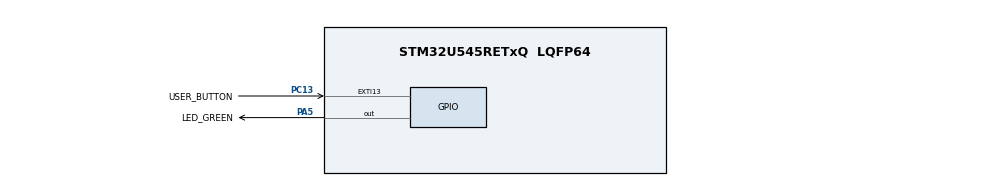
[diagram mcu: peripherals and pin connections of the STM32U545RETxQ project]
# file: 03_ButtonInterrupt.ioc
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CORTEX_M33_NS.userName=CORTEX_M33
Mcu.Family=STM32U5
Mcu.Name=STM32U545RETxQ
Mcu.Package=LQFP64
NVIC.EXTI13_IRQn=true\:0\:0\:false\:false\:true\:true\:true\:true
NVIC.PriorityGroup=NVIC_PRIORITYGROUP_4
PA5.GPIO_Label=LED_GREEN
PA5.GPIO_PuPd=GPIO_PULLUP
PA5.GPIO_Speed=GPIO_SPEED_FREQ_HIGH
PA5.Signal=GPIO_Output
PC13.GPIO_Label=USER_BUTTON
PC13.GPIO_ModeDefaultEXTI=GPIO_MODE_IT_FALLING
PC13.Signal=GPXTI13
PWR.PowerMode=PWR_SMPS_SUPPLY
ProjectManager.HeapSize=0x200
ProjectManager.StackSize=0x400
ProjectManager.TargetToolchain=STM32CubeIDE
RCC.ADCFreq_Value=16000000
RCC.DACCLockSelectionVirtual=RCC_DAC1CLKSOURCE_LSI
RCC.DACCLockSelectionVirtualString=RCC_DAC1CLKSOURCE_LSI
RCC.EPOD_VALUE=4000000
RCC.HSE_VALUE=16000000
RCC.HSI48_VALUE=48000000
RCC.HSI_VALUE=16000000
RCC.LSE_VALUE=32768
RCC.LSIDIV_VALUE=32000
RCC.MSI_VALUE=4000000
RCC.USBFreq_Value=48000000
RCC.VCOOutputFreq_Value=516000000
VP_ICACHE_VS_ICACHE.Mode=DirectMappedCache
VP_LPBAMQUEUE_VS_QUEUE.Mode=QUEUEMODE
VP_LPBAM_VS_SIG1.Mode=SmartRun
VP_LPBAM_VS_SIG4.Mode=LPDMA1
VP_MEMORYMAP_VS_MEMORYMAP.Mode=CurAppReg
VP_NUCLEO-U545RE-Q_VS_BSP_COMMON.Mode=COMMON
VP_PWR_VS_LPOM.Mode=PowerOptimisation
VP_PWR_VS_SECSignals.Mode=Security/Privilege
board=NUCLEO-U545RE-Q

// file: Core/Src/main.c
/* USER CODE BEGIN Header */
/**
 ******************************************************************************
 * @file           : main.c
 * @brief          : Main program body
 ******************************************************************************
 * @attention
 *
 * Copyright (c) 2025 STMicroelectronics.
 * All rights reserved.
 *
 * This software is licensed under terms that can be found in the LICENSE file
 * in the root directory of this software component.
 * If no LICENSE file comes with this software, it is provided AS-IS.
 *
 ******************************************************************************
 */
/* USER CODE END Header */
#include <CustomAssert.h>
#include "main.h"
#include "gpio.h"
#include "icache.h"

/* USER CODE BEGIN Includes */
#include "../../User_App/IsrHandler/IsrHandler.h"
#include "../../User_App/Profiler/Profiler.h"
#include "../../User_App/UserMain/UserMain.h"

/* USER CODE END Includes */

void SystemClock_Config(void);
static void SystemPower_Config(void);

int main(void) {

  /* MCU Configuration--------------------------------------------------------*/

  /* Reset of all peripherals, Initializes the Flash interface and the Systick.
   */
  HAL_Init();

  /* Configure the System Power */
  SystemPower_Config();

  /* Configure the system clock */
  SystemClock_Config();

  /* Initialize all configured peripherals */
  MX_GPIO_Init();
  MX_ICACHE_Init();
  /* USER CODE BEGIN 2 */

  UserMain();

  // From here the execution is in the user application
  // The user application should not return to this point

  /* USER CODE END 2 */

  /* Infinite loop */
  while (1) {

  }
}

void SystemClock_Config(void) {
  RCC_OscInitTypeDef RCC_OscInitStruct = {0};
  RCC_ClkInitTypeDef RCC_ClkInitStruct = {0};

  /** Configure the main internal regulator output voltage
   */
  if (HAL_PWREx_ControlVoltageScaling(PWR_REGULATOR_VOLTAGE_SCALE1) != HAL_OK) {
    Error_Handler();
  }

  /** Initializes the CPU, AHB and APB buses clocks
   */
  RCC_OscInitStruct.OscillatorType = RCC_OSCILLATORTYPE_MSI;
  RCC_OscInitStruct.MSIState = RCC_MSI_ON;
  RCC_OscInitStruct.MSICalibrationValue = RCC_MSICALIBRATION_DEFAULT;
  RCC_OscInitStruct.MSIClockRange = RCC_MSIRANGE_0;
  RCC_OscInitStruct.PLL.PLLState = RCC_PLL_ON;
  RCC_OscInitStruct.PLL.PLLSource = RCC_PLLSOURCE_MSI;
  RCC_OscInitStruct.PLL.PLLMBOOST = RCC_PLLMBOOST_DIV4;
  RCC_OscInitStruct.PLL.PLLM = 3;
  RCC_OscInitStruct.PLL.PLLN = 10;
  RCC_OscInitStruct.PLL.PLLP = 2;
  RCC_OscInitStruct.PLL.PLLQ = 2;
  RCC_OscInitStruct.PLL.PLLR = 1;
  RCC_OscInitStruct.PLL.PLLRGE = RCC_PLLVCIRANGE_1;
  RCC_OscInitStruct.PLL.PLLFRACN = 0;
  if (HAL_RCC_OscConfig(&RCC_OscInitStruct) != HAL_OK) {
    Error_Handler();
  }

  /** Initializes the CPU, AHB and APB buses clocks
   */
  RCC_ClkInitStruct.ClockType = RCC_CLOCKTYPE_HCLK | RCC_CLOCKTYPE_SYSCLK |
                                RCC_CLOCKTYPE_PCLK1 | RCC_CLOCKTYPE_PCLK2 |
                                RCC_CLOCKTYPE_PCLK3;
  RCC_ClkInitStruct.SYSCLKSource = RCC_SYSCLKSOURCE_PLLCLK;
  RCC_ClkInitStruct.AHBCLKDivider = RCC_SYSCLK_DIV1;
  RCC_ClkInitStruct.APB1CLKDivider = RCC_HCLK_DIV1;
  RCC_ClkInitStruct.APB2CLKDivider = RCC_HCLK_DIV1;
  RCC_ClkInitStruct.APB3CLKDivider = RCC_HCLK_DIV1;

  if (HAL_RCC_ClockConfig(&RCC_ClkInitStruct, FLASH_LATENCY_4) != HAL_OK) {
    Error_Handler();
  }
}

/**
 * @brief Power Configuration
 * @retval None
 */
static void SystemPower_Config(void) {

  /*
   * Switch to SMPS regulator instead of LDO
   */
  if (HAL_PWREx_ConfigSupply(PWR_SMPS_SUPPLY) != HAL_OK) {
    Error_Handler();
  }
}

/* USER CODE BEGIN 4 */
void HAL_GPIO_EXTI_Rising_Callback(uint16_t GPIO_Pin) {
  if (USER_BUTTON_Pin == GPIO_Pin) {
    IsrHandler_DispatchIsr(E_ISR_ID_BUTTON_EXTI);
  }
}

/* USER CODE END 4 */

void Error_Handler(void) {
  __disable_irq();
  while (1) {
  }
}
#ifdef USE_FULL_ASSERT
/**
 * @brief  Reports the name of the source file and the source line number
 *         where the assert_param error has occurred.
 * @param  file: pointer to the source file name
 * @param  line: assert_param error line source number
 * @retval None
 */
void assert_failed(uint8_t *file, uint32_t line) {
  /* USER CODE BEGIN 6 */
  custom_assert_failed("stm32 assert", (char *)file, line);
  /* USER CODE END 6 */
}
#endif /* USE_FULL_ASSERT */
